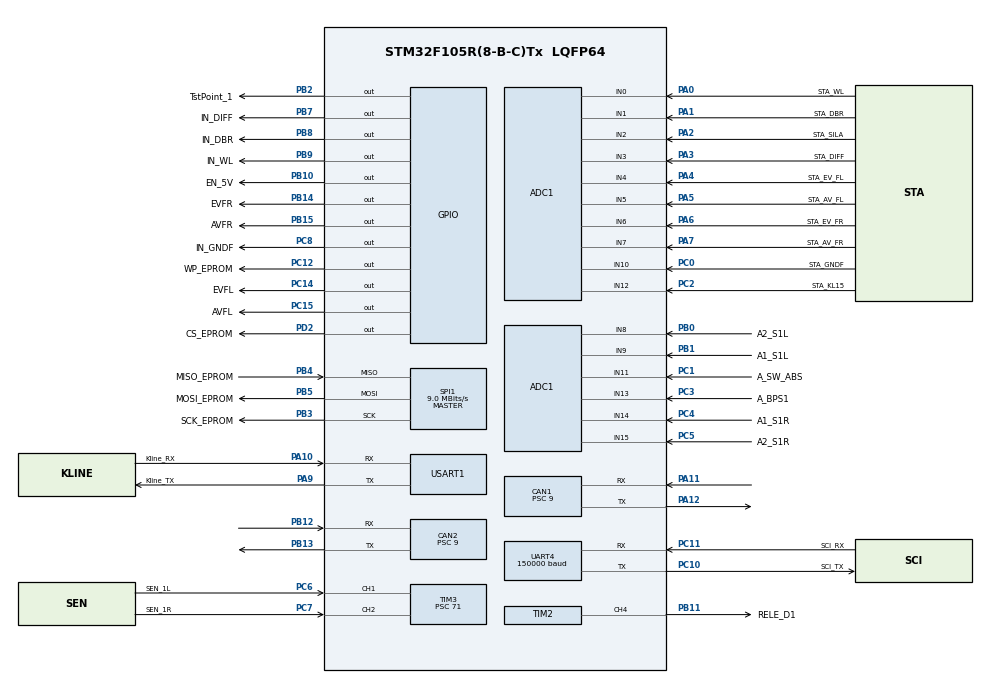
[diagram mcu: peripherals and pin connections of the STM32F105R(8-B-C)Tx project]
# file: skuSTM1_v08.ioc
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ADC1.Channel-0\#ChannelRegularConversion=ADC_CHANNEL_0
ADC1.Channel-1\#ChannelRegularConversion=ADC_CHANNEL_1
ADC1.Channel-10\#ChannelRegularConversion=ADC_CHANNEL_10
ADC1.Channel-11\#ChannelRegularConversion=ADC_CHANNEL_11
ADC1.Channel-12\#ChannelRegularConversion=ADC_CHANNEL_12
ADC1.Channel-13\#ChannelRegularConversion=ADC_CHANNEL_13
ADC1.Channel-14\#ChannelRegularConversion=ADC_CHANNEL_14
ADC1.Channel-15\#ChannelRegularConversion=ADC_CHANNEL_15
ADC1.Channel-2\#ChannelRegularConversion=ADC_CHANNEL_2
ADC1.Channel-3\#ChannelRegularConversion=ADC_CHANNEL_3
ADC1.Channel-4\#ChannelRegularConversion=ADC_CHANNEL_4
ADC1.Channel-5\#ChannelRegularConversion=ADC_CHANNEL_5
ADC1.Channel-6\#ChannelRegularConversion=ADC_CHANNEL_6
ADC1.Channel-7\#ChannelRegularConversion=ADC_CHANNEL_7
ADC1.Channel-8\#ChannelRegularConversion=ADC_CHANNEL_8
ADC1.Channel-9\#ChannelRegularConversion=ADC_CHANNEL_9
ADC1.ContinuousConvMode=DISABLE
ADC1.DataAlign=ADC_DATAALIGN_RIGHT
ADC1.DiscontinuousConvMode=DISABLE
ADC1.EnableAnalogWatchDog=false
ADC1.EnableRegularConversion=ENABLE
ADC1.ExternalTrigConv=ADC_SOFTWARE_START
ADC1.InjNumberOfConversion=0
ADC1.NbrOfConversion=16
ADC1.NbrOfConversionFlag=1
ADC1.Rank-0\#ChannelRegularConversion=1
ADC1.Rank-1\#ChannelRegularConversion=2
ADC1.Rank-10\#ChannelRegularConversion=11
ADC1.Rank-11\#ChannelRegularConversion=12
ADC1.Rank-12\#ChannelRegularConversion=13
ADC1.Rank-13\#ChannelRegularConversion=14
ADC1.Rank-14\#ChannelRegularConversion=15
ADC1.Rank-15\#ChannelRegularConversion=16
ADC1.Rank-2\#ChannelRegularConversion=3
ADC1.Rank-3\#ChannelRegularConversion=4
ADC1.Rank-4\#ChannelRegularConversion=5
ADC1.Rank-5\#ChannelRegularConversion=6
ADC1.Rank-6\#ChannelRegularConversion=7
ADC1.Rank-7\#ChannelRegularConversion=8
ADC1.Rank-8\#ChannelRegularConversion=9
ADC1.Rank-9\#ChannelRegularConversion=10
ADC1.SamplingTime-0\#ChannelRegularConversion=ADC_SAMPLETIME_41CYCLES_5
ADC1.SamplingTime-1\#ChannelRegularConversion=ADC_SAMPLETIME_41CYCLES_5
ADC1.SamplingTime-10\#ChannelRegularConversion=ADC_SAMPLETIME_41CYCLES_5
ADC1.SamplingTime-11\#ChannelRegularConversion=ADC_SAMPLETIME_41CYCLES_5
ADC1.SamplingTime-12\#ChannelRegularConversion=ADC_SAMPLETIME_41CYCLES_5
ADC1.SamplingTime-13\#ChannelRegularConversion=ADC_SAMPLETIME_41CYCLES_5
ADC1.SamplingTime-14\#ChannelRegularConversion=ADC_SAMPLETIME_41CYCLES_5
ADC1.SamplingTime-15\#ChannelRegularConversion=ADC_SAMPLETIME_41CYCLES_5
ADC1.SamplingTime-2\#ChannelRegularConversion=ADC_SAMPLETIME_41CYCLES_5
ADC1.SamplingTime-3\#ChannelRegularConversion=ADC_SAMPLETIME_41CYCLES_5
ADC1.SamplingTime-4\#ChannelRegularConversion=ADC_SAMPLETIME_41CYCLES_5
ADC1.SamplingTime-5\#ChannelRegularConversion=ADC_SAMPLETIME_41CYCLES_5
ADC1.SamplingTime-6\#ChannelRegularConversion=ADC_SAMPLETIME_41CYCLES_5
ADC1.SamplingTime-7\#ChannelRegularConversion=ADC_SAMPLETIME_41CYCLES_5
ADC1.SamplingTime-8\#ChannelRegularConversion=ADC_SAMPLETIME_41CYCLES_5
ADC1.SamplingTime-9\#ChannelRegularConversion=ADC_SAMPLETIME_41CYCLES_5
ADC1.ScanConvMode=ADC_SCAN_ENABLE
ADC1.master=1
CAN1.ABOM=ENABLE
CAN1.BS1=CAN_BS1_8TQ
CAN1.BS2=CAN_BS2_7TQ
CAN1.CalculateTimeBit=4000
CAN1.CalculateTimeQuantum=250.0
CAN1.Prescaler=9
CAN2.ABOM=ENABLE
CAN2.BS1=CAN_BS1_8TQ
CAN2.BS2=CAN_BS2_7TQ
CAN2.CalculateTimeBit=4000
CAN2.CalculateTimeQuantum=250.0
CAN2.Mode=CAN_MODE_NORMAL
CAN2.Prescaler=9
Dma.ADC1.1.Direction=DMA_PERIPH_TO_MEMORY
Dma.ADC1.1.Instance=DMA1_Channel1
Dma.ADC1.1.MemDataAlignment=DMA_MDATAALIGN_HALFWORD
Dma.ADC1.1.MemInc=DMA_MINC_ENABLE
Dma.ADC1.1.Mode=DMA_NORMAL
Dma.ADC1.1.PeriphDataAlignment=DMA_PDATAALIGN_HALFWORD
Dma.ADC1.1.PeriphInc=DMA_PINC_DISABLE
Dma.ADC1.1.Priority=DMA_PRIORITY_LOW
Dma.MEMTOMEM.0.Direction=DMA_MEMORY_TO_MEMORY
Dma.MEMTOMEM.0.Instance=DMA1_Channel6
Dma.MEMTOMEM.0.MemDataAlignment=DMA_MDATAALIGN_WORD
Dma.MEMTOMEM.0.MemInc=DMA_MINC_ENABLE
Dma.MEMTOMEM.0.Mode=DMA_NORMAL
Dma.MEMTOMEM.0.PeriphDataAlignment=DMA_PDATAALIGN_WORD
Dma.MEMTOMEM.0.PeriphInc=DMA_PINC_ENABLE
Dma.MEMTOMEM.0.Priority=DMA_PRIORITY_LOW
Dma.Request0=MEMTOMEM
Dma.Request1=ADC1
Dma.Request2=USART1_RX
Dma.Request3=USART1_TX
Dma.Request4=SPI1_RX
Dma.Request5=SPI1_TX
Dma.Request6=UART4_RX
Dma.Request7=UART4_TX
Dma.SPI1_RX.4.Direction=DMA_PERIPH_TO_MEMORY
Dma.SPI1_RX.4.Instance=DMA1_Channel2
Dma.SPI1_RX.4.MemDataAlignment=DMA_MDATAALIGN_BYTE
Dma.SPI1_RX.4.MemInc=DMA_MINC_ENABLE
Dma.SPI1_RX.4.Mode=DMA_NORMAL
Dma.SPI1_RX.4.PeriphDataAlignment=DMA_PDATAALIGN_BYTE
Dma.SPI1_RX.4.PeriphInc=DMA_PINC_DISABLE
Dma.SPI1_RX.4.Priority=DMA_PRIORITY_LOW
Dma.SPI1_TX.5.Direction=DMA_MEMORY_TO_PERIPH
Dma.SPI1_TX.5.Instance=DMA1_Channel3
Dma.SPI1_TX.5.MemDataAlignment=DMA_MDATAALIGN_BYTE
Dma.SPI1_TX.5.MemInc=DMA_MINC_ENABLE
Dma.SPI1_TX.5.Mode=DMA_NORMAL
Dma.SPI1_TX.5.PeriphDataAlignment=DMA_PDATAALIGN_BYTE
Dma.SPI1_TX.5.PeriphInc=DMA_PINC_DISABLE
Dma.SPI1_TX.5.Priority=DMA_PRIORITY_LOW
Dma.UART4_RX.6.Direction=DMA_PERIPH_TO_MEMORY
Dma.UART4_RX.6.Instance=DMA2_Channel3
Dma.UART4_RX.6.MemDataAlignment=DMA_MDATAALIGN_BYTE
Dma.UART4_RX.6.MemInc=DMA_MINC_ENABLE
Dma.UART4_RX.6.Mode=DMA_NORMAL
Dma.UART4_RX.6.PeriphDataAlignment=DMA_PDATAALIGN_BYTE
Dma.UART4_RX.6.PeriphInc=DMA_PINC_DISABLE
Dma.UART4_RX.6.Priority=DMA_PRIORITY_HIGH
Dma.UART4_TX.7.Direction=DMA_MEMORY_TO_PERIPH
Dma.UART4_TX.7.Instance=DMA2_Channel5
Dma.UART4_TX.7.MemDataAlignment=DMA_MDATAALIGN_BYTE
Dma.UART4_TX.7.MemInc=DMA_MINC_ENABLE
Dma.UART4_TX.7.Mode=DMA_NORMAL
Dma.UART4_TX.7.PeriphDataAlignment=DMA_PDATAALIGN_BYTE
Dma.UART4_TX.7.PeriphInc=DMA_PINC_DISABLE
Dma.UART4_TX.7.Priority=DMA_PRIORITY_MEDIUM
Dma.USART1_RX.2.Direction=DMA_PERIPH_TO_MEMORY
Dma.USART1_RX.2.Instance=DMA1_Channel5
Dma.USART1_RX.2.MemDataAlignment=DMA_MDATAALIGN_BYTE
Dma.USART1_RX.2.MemInc=DMA_MINC_ENABLE
Dma.USART1_RX.2.Mode=DMA_NORMAL
Dma.USART1_RX.2.PeriphDataAlignment=DMA_PDATAALIGN_BYTE
Dma.USART1_RX.2.PeriphInc=DMA_PINC_DISABLE
Dma.USART1_RX.2.Priority=DMA_PRIORITY_HIGH
Dma.USART1_TX.3.Direction=DMA_MEMORY_TO_PERIPH
Dma.USART1_TX.3.Instance=DMA1_Channel4
Dma.USART1_TX.3.MemDataAlignment=DMA_MDATAALIGN_BYTE
Dma.USART1_TX.3.MemInc=DMA_MINC_ENABLE
Dma.USART1_TX.3.Mode=DMA_NORMAL
Dma.USART1_TX.3.PeriphDataAlignment=DMA_PDATAALIGN_BYTE
Dma.USART1_TX.3.PeriphInc=DMA_PINC_DISABLE
Dma.USART1_TX.3.Priority=DMA_PRIORITY_MEDIUM
IWDG.Prescaler=IWDG_PRESCALER_32
Mcu.Family=STM32F1
Mcu.Name=STM32F105R(8-B-C)Tx
Mcu.Package=LQFP64
NVIC.ADC1_2_IRQn=true\:0\:3\:true\:true\:true\:22\:true
NVIC.CAN1_RX0_IRQn=true\:2\:0\:true\:true\:true\:4\:true
NVIC.CAN1_RX1_IRQn=true\:2\:0\:true\:true\:true\:5\:true
NVIC.CAN1_SCE_IRQn=true\:3\:0\:true\:true\:true\:6\:true
NVIC.CAN1_TX_IRQn=true\:3\:0\:true\:true\:true\:3\:true
NVIC.CAN2_RX0_IRQn=true\:2\:0\:true\:true\:true\:13\:true
NVIC.CAN2_RX1_IRQn=true\:2\:0\:true\:true\:true\:15\:true
NVIC.CAN2_SCE_IRQn=true\:3\:0\:true\:true\:true\:14\:true
NVIC.CAN2_TX_IRQn=true\:2\:0\:true\:true\:true\:12\:true
NVIC.DMA1_Channel1_IRQn=true\:0\:3\:true\:true\:true\:2\:false
NVIC.DMA1_Channel2_IRQn=true\:1\:0\:true\:true\:true\:20\:false
NVIC.DMA1_Channel3_IRQn=true\:1\:0\:true\:true\:true\:17\:true
NVIC.DMA1_Channel4_IRQn=true\:2\:2\:true\:true\:true\:21\:true
NVIC.DMA1_Channel5_IRQn=true\:2\:3\:true\:true\:true\:24\:false
NVIC.DMA1_Channel6_IRQn=true\:3\:0\:true\:true\:true\:25\:true
NVIC.DMA2_Channel3_IRQn=true\:0\:1\:false\:true\:true\:9\:false
NVIC.DMA2_Channel5_IRQn=true\:0\:1\:true\:true\:true\:10\:false
NVIC.FLASH_IRQn=true\:1\:0\:true\:true\:true\:1\:true
NVIC.PriorityGroup=NVIC_PRIORITYGROUP_2
NVIC.SPI1_IRQn=true\:1\:0\:true\:true\:true\:19\:true
NVIC.TIM1_CC_IRQn=true\:1\:0\:true\:true\:true\:18\:true
NVIC.TIM3_IRQn=true\:1\:1\:true\:true\:true\:16\:true
NVIC.TIM4_IRQn=true\:1\:2\:true\:true\:true\:23\:true
NVIC.TIM6_IRQn=true\:1\:0\:true\:true\:true\:7\:true
NVIC.TIM7_IRQn=true\:3\:0\:true\:true\:true\:8\:true
NVIC.UART4_IRQn=true\:0\:1\:false\:true\:true\:11\:true
NVIC.USART1_IRQn=true\:2\:0\:true\:false\:true\:true
PA0-WKUP.GPIO_Label=STA_WL
PA0-WKUP.GPIO_Mode=GPIO_MODE_ANALOG
PA0-WKUP.Signal=ADCx_IN0
PA1.GPIO_Label=STA_DBR
PA1.Signal=ADCx_IN1
PA10.GPIO_Label=Kline_RX
PA10.Mode=Asynchronous
PA10.Signal=USART1_RX
PA11.GPIO_Mode=GPIO_MODE_INPUT
PA11.GPIO_PuPd=GPIO_NOPULL
PA11.Mode=Master
PA11.Signal=CAN1_RX
PA12.GPIO_Mode=GPIO_MODE_AF_PP
PA12.GPIO_Speed=GPIO_SPEED_FREQ_HIGH
PA12.Mode=Master
PA12.Signal=CAN1_TX
PA2.GPIO_Label=STA_SILA
PA2.GPIO_Mode=GPIO_MODE_ANALOG
PA2.Signal=ADCx_IN2
PA3.GPIO_Label=STA_DIFF
PA3.Signal=ADCx_IN3
PA4.GPIO_Label=STA_EV_FL
PA4.Signal=ADCx_IN4
PA5.GPIO_Label=STA_AV_FL
PA5.Signal=ADCx_IN5
PA6.GPIO_Label=STA_EV_FR
PA6.Signal=ADCx_IN6
PA7.GPIO_Label=STA_AV_FR
PA7.Signal=ADCx_IN7
PA9.GPIO_Label=Kline_TX
PA9.Mode=Asynchronous
PA9.Signal=USART1_TX
PB0.GPIO_Label=A2_S1L
PB0.Signal=ADCx_IN8
PB1.GPIO_Label=A1_S1L
PB1.Signal=ADCx_IN9
PB10.GPIO_Label=EN_5V
PB10.GPIO_ModeDefaultOutputPP=GPIO_MODE_OUTPUT_PP
PB10.PinState=GPIO_PIN_SET
PB10.Signal=GPIO_Output
PB11.GPIO_Label=RELE_D1
PB11.Signal=S_TIM2_CH4
PB12.GPIO_Mode=GPIO_MODE_INPUT
PB12.Mode=Slave
PB12.Signal=CAN2_RX
PB13.Mode=Slave
PB13.Signal=CAN2_TX
PB14.GPIO_Label=EVFR
PB14.Signal=GPIO_Output
PB15.GPIO_Label=AVFR
PB15.Signal=GPIO_Output
PB2.GPIO_Label=TstPoint_1
PB2.Signal=GPIO_Output
PB3.GPIO_Label=SCK_EPROM
PB3.GPIO_Speed=GPIO_SPEED_FREQ_HIGH
PB3.Mode=Full_Duplex_Master
PB3.Signal=SPI1_SCK
PB4.GPIO_Label=MISO_EPROM
PB4.Mode=Full_Duplex_Master
PB4.Signal=SPI1_MISO
PB5.GPIO_Label=MOSI_EPROM
PB5.Mode=Full_Duplex_Master
PB5.Signal=SPI1_MOSI
PB7.GPIO_Label=IN_DIFF
PB7.Signal=GPIO_Output
PB8.GPIO_Label=IN_DBR
PB8.Signal=GPIO_Output
PB9.GPIO_Label=IN_WL
PB9.PinState=GPIO_PIN_SET
PB9.Signal=GPIO_Output
PC0.GPIO_Label=STA_GNDF
PC0.Signal=ADCx_IN10
PC1.GPIO_Label=A_SW_ABS
PC1.Signal=ADCx_IN11
PC10.GPIO_Label=SCI_TX
PC10.Mode=Asynchronous
PC10.Signal=UART4_TX
PC11.GPIO_Label=SCI_RX
PC11.GPIO_PuPd=GPIO_PULLUP
PC11.Mode=Asynchronous
PC11.Signal=UART4_RX
PC12.GPIO_Label=WP_EPROM
PC12.Signal=GPIO_Output
PC14-OSC32_IN.GPIO_Label=EVFL
PC14-OSC32_IN.Signal=GPIO_Output
PC15-OSC32_OUT.GPIO_Label=AVFL
PC15-OSC32_OUT.Signal=GPIO_Output
PC2.GPIO_Label=STA_KL15
PC2.Signal=ADCx_IN12
PC3.GPIO_Label=A_BPS1
PC3.Signal=ADCx_IN13
PC4.GPIO_Label=A1_S1R
PC4.Signal=ADCx_IN14
PC5.GPIO_Label=A2_S1R
PC5.Signal=ADCx_IN15
PC6.GPIO_Label=SEN_1L
PC6.Signal=S_TIM3_CH1
PC7.GPIO_Label=SEN_1R
PC7.Signal=S_TIM3_CH2
PC8.GPIO_Label=IN_GNDF
PC8.GPIO_Speed=GPIO_SPEED_FREQ_HIGH
PC8.PinState=GPIO_PIN_SET
PC8.Signal=GPIO_Output
PD0-OSC_IN.Mode=HSE-External-Oscillator
PD0-OSC_IN.Signal=RCC_OSC_IN
PD1-OSC_OUT.Mode=HSE-External-Oscillator
PD1-OSC_OUT.Signal=RCC_OSC_OUT
PD2.GPIO_Label=CS_EPROM
PD2.GPIO_ModeDefaultOutputPP=GPIO_MODE_OUTPUT_PP
PD2.PinState=GPIO_PIN_SET
PD2.Signal=GPIO_Output
ProjectManager.HeapSize=0x200
ProjectManager.StackSize=0x400
ProjectManager.TargetToolchain=SW4STM32
RCC.ADCPresc=RCC_ADCPCLK2_DIV4
RCC.AHBFreq_Value=72000000
RCC.APB1CLKDivider=RCC_HCLK_DIV2
RCC.APB1Freq_Value=36000000
RCC.APB1TimFreq_Value=72000000
RCC.APB2CLKDivider=RCC_HCLK_DIV2
RCC.APB2Freq_Value=36000000
RCC.APB2TimFreq_Value=72000000
RCC.DATA_CACHE_ENABLE=1
RCC.HCLKFreq_Value=72000000
RCC.HSEDivPLL=RCC_HSE_PREDIV_DIV5
RCC.HSEUsed=1
RCC.HSE_Timout=10
RCC.INSTRUCTION_CACHE_ENABLE=1
RCC.LSE_Timout=10
RCC.PLL2Mul=RCC_PLL2_MUL10
RCC.PLLMUL=RCC_PLL_MUL9
RCC.PLLSourceVirtual=RCC_PLLSOURCE_HSE
RCC.PREFETCH_ENABLE=1
RCC.Prediv1Source=RCC_PREDIV1_SOURCE_PLL2
RCC.Prediv2=RCC_HSE_PREDIV2_DIV2
RCC.SYSCLKFreq_VALUE=72000000
RCC.SYSCLKSource=RCC_SYSCLKSOURCE_PLLCLK
RCC.USBFreq_Value=48000000
SH.ADCx_IN0.0=ADC1_IN0,IN0
SH.ADCx_IN1.0=ADC1_IN1,IN1
SH.ADCx_IN10.0=ADC1_IN10,IN10
SH.ADCx_IN11.0=ADC1_IN11,IN11
SH.ADCx_IN12.0=ADC1_IN12,IN12
SH.ADCx_IN13.0=ADC1_IN13,IN13
SH.ADCx_IN14.0=ADC1_IN14,IN14
SH.ADCx_IN15.0=ADC1_IN15,IN15
SH.ADCx_IN2.0=ADC1_IN2,IN2
SH.ADCx_IN3.0=ADC1_IN3,IN3
SH.ADCx_IN4.0=ADC1_IN4,IN4
SH.ADCx_IN5.0=ADC1_IN5,IN5
SH.ADCx_IN6.0=ADC1_IN6,IN6
SH.ADCx_IN7.0=ADC1_IN7,IN7
SH.ADCx_IN8.0=ADC1_IN8,IN8
SH.ADCx_IN9.0=ADC1_IN9,IN9
SH.S_TIM2_CH4.0=TIM2_CH4,PWM Generation4 CH4
SH.S_TIM3_CH1.0=TIM3_CH1,Input_Capture1_from_TI1
SH.S_TIM3_CH2.0=TIM3_CH2,Input_Capture2_from_TI2
SPI1.BaudRatePrescaler=SPI_BAUDRATEPRESCALER_4
SPI1.CLKPhase=SPI_PHASE_1EDGE
SPI1.CLKPolarity=SPI_POLARITY_LOW
SPI1.CalculateBaudRate=9.0 MBits/s
SPI1.Direction=SPI_DIRECTION_2LINES
SPI1.Mode=SPI_MODE_MASTER
SPI1.VirtualType=VM_MASTER
TIM1.Channel-Output\ Compare1\ No\ Output=TIM_CHANNEL_1
TIM1.Channel-Output\ Compare2\ No\ Output=TIM_CHANNEL_2
TIM1.Channel-Output\ Compare3\ No\ Output=TIM_CHANNEL_3
TIM1.Channel-Output\ Compare4\ No\ Output=TIM_CHANNEL_4
TIM1.Period=0xFFFF
TIM1.Prescaler=71
TIM2.Channel-PWM\ Generation4\ CH4=TIM_CHANNEL_4
TIM2.OCPolarity_4=TIM_OCPOLARITY_LOW
TIM2.Period=3600
TIM2.Prescaler=0
TIM3.AutoReloadPreload=TIM_AUTORELOAD_PRELOAD_DISABLE
TIM3.Channel-Input_Capture1_from_TI1=TIM_CHANNEL_1
TIM3.Channel-Input_Capture2_from_TI2=TIM_CHANNEL_2
TIM3.ICFilter_CH1=15
TIM3.ICFilter_CH2=15
TIM3.ICPolarity_CH1=TIM_INPUTCHANNELPOLARITY_FALLING
TIM3.ICPolarity_CH2=TIM_INPUTCHANNELPOLARITY_FALLING
TIM3.Period=0xFFFF
TIM3.Prescaler=71
TIM3.TIM_MasterSlaveMode=TIM_MASTERSLAVEMODE_DISABLE
TIM4.AutoReloadPreload=TIM_AUTORELOAD_PRELOAD_ENABLE
TIM4.Channel-Output\ Compare3\ No\ Output=TIM_CHANNEL_3
TIM4.Period=0xFFFF
TIM4.Prescaler=71
TIM4.Pulse-Output\ Compare3\ No\ Output=300
TIM6.AutoReloadPreload=TIM_AUTORELOAD_PRELOAD_DISABLE
TIM6.Period=5000
TIM6.Prescaler=71
TIM6.TIM_MasterOutputTrigger=TIM_TRGO_RESET
TIM7.Period=100
TIM7.Prescaler=71
UART4.BaudRate=150000
UART4.VirtualMode=Asynchronous
USART1.VirtualMode=VM_ASYNC
VP_ADC1_TempSens_Input.Mode=IN-TempSens
VP_CRC_VS_CRC.Mode=CRC_Activate
VP_IWDG_VS_IWDG.Mode=IWDG_Activate
VP_SYS_VS_ND.Mode=No_Debug
VP_TIM1_VS_ClockSourceINT.Mode=Internal
VP_TIM1_VS_no_output1.Mode=Output Compare1 No Output
VP_TIM1_VS_no_output2.Mode=Output Compare2 No Output
VP_TIM1_VS_no_output3.Mode=Output Compare3 No Output
VP_TIM1_VS_no_output4.Mode=Output Compare4 No Output
VP_TIM2_VS_ClockSourceINT.Mode=Internal
VP_TIM3_VS_ClockSourceINT.Mode=Internal
VP_TIM4_VS_ClockSourceINT.Mode=Internal
VP_TIM4_VS_no_output3.Mode=Output Compare3 No Output
VP_TIM6_VS_ClockSourceINT.Mode=Enable_Timer
VP_TIM7_VS_ClockSourceINT.Mode=Enable_Timer
board=skuSTM1_v08

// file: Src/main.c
/**
  ******************************************************************************
  * @file           : main.c
  * @brief          : Main program body
  ******************************************************************************
  ** This notice applies to any and all portions of this file
  * that are not between comment pairs USER CODE BEGIN and
  * USER CODE END. Other portions of this file, whether
  * inserted by the user or by software development tools
  * are owned by their respective copyright owners.
  *
  * COPYRIGHT(c) 2025 STMicroelectronics
  *
  * Redistribution and use in source and binary forms, with or without modification,
  * are permitted provided that the following conditions are met:
  *   1. Redistributions of source code must retain the above copyright notice,
  *      this list of conditions and the following disclaimer.
  *   2. Redistributions in binary form must reproduce the above copyright notice,
  *      this list of conditions and the following disclaimer in the documentation
  *      and/or other materials provided with the distribution.
  *   3. Neither the name of STMicroelectronics nor the names of its contributors
  *      may be used to endorse or promote products derived from this software
  *      without specific prior written permission.
  *
  * THIS SOFTWARE IS PROVIDED BY THE COPYRIGHT HOLDERS AND CONTRIBUTORS "AS IS"
  * AND ANY EXPRESS OR IMPLIED WARRANTIES, INCLUDING, BUT NOT LIMITED TO, THE
  * IMPLIED WARRANTIES OF MERCHANTABILITY AND FITNESS FOR A PARTICULAR PURPOSE ARE
  * DISCLAIMED. IN NO EVENT SHALL THE COPYRIGHT HOLDER OR CONTRIBUTORS BE LIABLE
  * FOR ANY DIRECT, INDIRECT, INCIDENTAL, SPECIAL, EXEMPLARY, OR CONSEQUENTIAL
  * DAMAGES (INCLUDING, BUT NOT LIMITED TO, PROCUREMENT OF SUBSTITUTE GOODS OR
  * SERVICES; LOSS OF USE, DATA, OR PROFITS; OR BUSINESS INTERRUPTION) HOWEVER
  * CAUSED AND ON ANY THEORY OF LIABILITY, WHETHER IN CONTRACT, STRICT LIABILITY,
  * OR TORT (INCLUDING NEGLIGENCE OR OTHERWISE) ARISING IN ANY WAY OUT OF THE USE
  * OF THIS SOFTWARE, EVEN IF ADVISED OF THE POSSIBILITY OF SUCH DAMAGE.
  *
  ******************************************************************************
  */
#include "main.h"
#include "stm32f1xx_hal.h"

/* USER CODE BEGIN Includes */
#include "MyTypeDef.h"
#include "MyPGM.h"
#include "MySystem.h"
#include "MyFunc.h"
#include "MyVAR.h"

/* USER CODE END Includes */

ADC_HandleTypeDef hadc1;
DMA_HandleTypeDef hdma_adc1;

CAN_HandleTypeDef hcan1;
CAN_HandleTypeDef hcan2;

CRC_HandleTypeDef hcrc;

IWDG_HandleTypeDef hiwdg;

SPI_HandleTypeDef hspi1;
DMA_HandleTypeDef hdma_spi1_rx;
DMA_HandleTypeDef hdma_spi1_tx;

TIM_HandleTypeDef htim1;
TIM_HandleTypeDef htim2;
TIM_HandleTypeDef htim3;
TIM_HandleTypeDef htim4;
TIM_HandleTypeDef htim6;
TIM_HandleTypeDef htim7;

UART_HandleTypeDef huart4;
UART_HandleTypeDef huart1;
DMA_HandleTypeDef hdma_uart4_rx;
DMA_HandleTypeDef hdma_uart4_tx;
DMA_HandleTypeDef hdma_usart1_rx;
DMA_HandleTypeDef hdma_usart1_tx;

DMA_HandleTypeDef hdma_memtomem_dma1_channel6;

/* USER CODE BEGIN PV */
/* Private variables ---------------------------------------------------------*/

/* USER CODE END PV */

void SystemClock_Config(void);
static void MX_GPIO_Init(void);
static void MX_DMA_Init(void);
static void MX_CRC_Init(void);
static void MX_ADC1_Init(void);
static void MX_TIM6_Init(void);
static void MX_UART4_Init(void);
static void MX_TIM7_Init(void);
static void MX_TIM1_Init(void);
static void MX_CAN1_Init(void);
static void MX_IWDG_Init(void);
static void MX_CAN2_Init(void);
static void MX_TIM3_Init(void);
static void MX_TIM4_Init(void);
static void MX_SPI1_Init(void);
static void MX_USART1_UART_Init(void);
static void MX_TIM2_Init(void);
static void MX_NVIC_Init(void);

void HAL_TIM_MspPostInit(TIM_HandleTypeDef *htim);

/* USER CODE BEGIN PFP */
/* Private function prototypes -----------------------------------------------*/

/* USER CODE END PFP */

/* USER CODE BEGIN 0 */
extern uint8_t  PGM_Active;
extern uint8_t  CANS_InitState;
/* USER CODE END 0 */

int main(void)
{

  /* MCU Configuration----------------------------------------------------------*/

  /* Reset of all peripherals, Initializes the Flash interface and the Systick. */
  HAL_Init();

  /* USER CODE BEGIN Init */
#ifdef __MC_GD
uint32_t *FMC_WSEN;
      FMC_WSEN = (uint32_t*)0x400220FC;
      FLASH->KEYR = FLASH_KEY1;
      FLASH->KEYR = FLASH_KEY2;
      *FMC_WSEN = (uint32_t)1U;
#endif
  /* USER CODE END Init */

  /* Configure the system clock */
  SystemClock_Config();

  /* USER CODE BEGIN SysInit */
  // устанавливаем STA_CANTL_Pin для установки компаратора в 1
  // если резистор R152 0 (27Om)
/*GPIO_InitTypeDef GPIO_InitStruct;
      __HAL_RCC_GPIOB_CLK_ENABLE();
	  GPIO_InitStruct.Pin = CANTL_EN_Pin|STA_CANTL_Pin|TstPoint_2_Pin;
	  GPIO_InitStruct.Mode = GPIO_MODE_OUTPUT_PP;
	  GPIO_InitStruct.Speed = GPIO_SPEED_FREQ_LOW;
	  HAL_GPIO_Init(GPIOB, &GPIO_InitStruct);

      HAL_GPIO_WritePin(GPIOB, STA_CANTL_Pin, GPIO_PIN_SET);
      HAL_GPIO_WritePin(GPIOB, CANTL_EN_Pin, GPIO_PIN_SET);
	  while(!HAL_GPIO_ReadPin(GPIOB, CANT_RX_Pin));
*/
  /* USER CODE END SysInit */

  /* Initialize all configured peripherals */
  MX_GPIO_Init();
  MX_DMA_Init();
  MX_CRC_Init();
  MX_ADC1_Init();
  MX_TIM6_Init();
  MX_UART4_Init();
  MX_TIM7_Init();
  MX_TIM1_Init();
  MX_CAN1_Init();
  MX_IWDG_Init();
  MX_CAN2_Init();
  MX_TIM3_Init();
  MX_TIM4_Init();
  MX_SPI1_Init();
  MX_USART1_UART_Init();
  MX_TIM2_Init();

  /* Initialize interrupts */
  MX_NVIC_Init();
  /* USER CODE BEGIN 2 */
  CANS_InitState = HAL_CAN_GetState(&hcan1);

  if(!PGM_Active)  MyHallTab[14](); // My_Init();

  /* USER CODE END 2 */

  /* Infinite loop */
  while (1)
  {

  /* USER CODE BEGIN 3 */
	if(PGM_Active)
	{ // активен программатор
		 MyHallTab[19](); //My_UpGrade_STM();
	  // выход отсюда в программаторах Jump_To_App()
	}
	else MyHallTab[15](); //   My_Main();
  }
  /* USER CODE END 3 */

}

void SystemClock_Config(void)
{

  RCC_OscInitTypeDef RCC_OscInitStruct;
  RCC_ClkInitTypeDef RCC_ClkInitStruct;
  RCC_PeriphCLKInitTypeDef PeriphClkInit;

    /**Initializes the CPU, AHB and APB busses clocks
    */
  RCC_OscInitStruct.OscillatorType = RCC_OSCILLATORTYPE_LSI|RCC_OSCILLATORTYPE_HSE;
  RCC_OscInitStruct.HSEState = RCC_HSE_ON;
  RCC_OscInitStruct.HSEPredivValue = RCC_HSE_PREDIV_DIV4;
  RCC_OscInitStruct.HSIState = RCC_HSI_ON;
  RCC_OscInitStruct.LSIState = RCC_LSI_ON;
  RCC_OscInitStruct.Prediv1Source = RCC_PREDIV1_SOURCE_PLL2;
  RCC_OscInitStruct.PLL.PLLState = RCC_PLL_ON;
  RCC_OscInitStruct.PLL.PLLSource = RCC_PLLSOURCE_HSE;
  RCC_OscInitStruct.PLL.PLLMUL = RCC_PLL_MUL9;
  RCC_OscInitStruct.PLL2.PLL2State = RCC_PLL2_ON;
  RCC_OscInitStruct.PLL2.PLL2MUL = RCC_PLL2_MUL12;
  RCC_OscInitStruct.PLL2.HSEPrediv2Value = RCC_HSE_PREDIV2_DIV2;
  if (HAL_RCC_OscConfig(&RCC_OscInitStruct) != HAL_OK)
  {
    _Error_Handler(__FILE__, __LINE__);
  }

    /**Initializes the CPU, AHB and APB busses clocks
    */
  RCC_ClkInitStruct.ClockType = RCC_CLOCKTYPE_HCLK|RCC_CLOCKTYPE_SYSCLK
                              |RCC_CLOCKTYPE_PCLK1|RCC_CLOCKTYPE_PCLK2;
  RCC_ClkInitStruct.SYSCLKSource = RCC_SYSCLKSOURCE_PLLCLK;
  RCC_ClkInitStruct.AHBCLKDivider = RCC_SYSCLK_DIV1;
  RCC_ClkInitStruct.APB1CLKDivider = RCC_HCLK_DIV2;
  RCC_ClkInitStruct.APB2CLKDivider = RCC_HCLK_DIV2;

  if (HAL_RCC_ClockConfig(&RCC_ClkInitStruct, FLASH_LATENCY_2) != HAL_OK)
  {
    _Error_Handler(__FILE__, __LINE__);
  }

  PeriphClkInit.PeriphClockSelection = RCC_PERIPHCLK_ADC;
  PeriphClkInit.AdcClockSelection = RCC_ADCPCLK2_DIV6;
  if (HAL_RCCEx_PeriphCLKConfig(&PeriphClkInit) != HAL_OK)
  {
    _Error_Handler(__FILE__, __LINE__);
  }

    /**Configure the Systick interrupt time
    */
  HAL_SYSTICK_Config(HAL_RCC_GetHCLKFreq()/1000);

    /**Configure the Systick
    */
  HAL_SYSTICK_CLKSourceConfig(SYSTICK_CLKSOURCE_HCLK);

    /**Configure the Systick interrupt time
    */
  __HAL_RCC_PLLI2S_ENABLE();

  /* SysTick_IRQn interrupt configuration */
//  HAL_NVIC_SetPriority(SysTick_IRQn, 3, 0);
}

/**
  * @brief NVIC Configuration.
  * @retval None
  */
static void MX_NVIC_Init(void)
{
  /* FLASH_IRQn interrupt configuration */
  HAL_NVIC_SetPriority(FLASH_IRQn, 1, 0);
  HAL_NVIC_EnableIRQ(FLASH_IRQn);

  /* ADC1_2_IRQn interrupt configuration */
  HAL_NVIC_SetPriority(ADC1_2_IRQn, 0, 3);
  HAL_NVIC_EnableIRQ(ADC1_2_IRQn);
  /* DMA1_Channel1_IRQn interrupt configuration */
  HAL_NVIC_SetPriority(DMA1_Channel1_IRQn, 0, 3);
  HAL_NVIC_EnableIRQ(DMA1_Channel1_IRQn);

  /* CAN1_TX_IRQn interrupt configuration */
  HAL_NVIC_SetPriority(CAN1_TX_IRQn, 3, 0);
  HAL_NVIC_EnableIRQ(CAN1_TX_IRQn);
  /* CAN1_RX0_IRQn interrupt configuration */
  HAL_NVIC_SetPriority(CAN1_RX0_IRQn, 2, 0);
  HAL_NVIC_EnableIRQ(CAN1_RX0_IRQn);
  /* CAN1_RX1_IRQn interrupt configuration */
  HAL_NVIC_SetPriority(CAN1_RX1_IRQn, 2, 0);
  HAL_NVIC_EnableIRQ(CAN1_RX1_IRQn);
  /* CAN1_SCE_IRQn interrupt configuration */
  HAL_NVIC_SetPriority(CAN1_SCE_IRQn, 3, 0);
  HAL_NVIC_EnableIRQ(CAN1_SCE_IRQn);

  /* TIM6_IRQn interrupt configuration */
  HAL_NVIC_SetPriority(TIM6_IRQn, 1, 0);
  HAL_NVIC_EnableIRQ(TIM6_IRQn);
  /* TIM7_IRQn interrupt configuration */
  HAL_NVIC_SetPriority(TIM7_IRQn, 3, 0);
  HAL_NVIC_EnableIRQ(TIM7_IRQn);

  /* CAN2_TX_IRQn interrupt configuration */
  HAL_NVIC_SetPriority(CAN2_TX_IRQn, 2, 0);
  HAL_NVIC_EnableIRQ(CAN2_TX_IRQn);
  /* CAN2_RX0_IRQn interrupt configuration */
  HAL_NVIC_SetPriority(CAN2_RX0_IRQn, 2, 0);
  HAL_NVIC_EnableIRQ(CAN2_RX0_IRQn);
  /* CAN2_SCE_IRQn interrupt configuration */
  HAL_NVIC_SetPriority(CAN2_SCE_IRQn, 3, 0);
  HAL_NVIC_EnableIRQ(CAN2_SCE_IRQn);
  /* CAN2_RX1_IRQn interrupt configuration */
  HAL_NVIC_SetPriority(CAN2_RX1_IRQn, 2, 0);
  HAL_NVIC_EnableIRQ(CAN2_RX1_IRQn);

  /* TIM3_IRQn interrupt configuration */
  HAL_NVIC_SetPriority(TIM3_IRQn, 1, 1);
  HAL_NVIC_EnableIRQ(TIM3_IRQn);
  /* TIM1_CC_IRQn interrupt configuration */
  HAL_NVIC_SetPriority(TIM1_CC_IRQn, 1, 0);
  HAL_NVIC_EnableIRQ(TIM1_CC_IRQn);

  /* SPI1_IRQn interrupt configuration */
  HAL_NVIC_SetPriority(SPI1_IRQn, 1, 0);
  HAL_NVIC_EnableIRQ(SPI1_IRQn);
  /* DMA1_Channel2_IRQn interrupt configuration */
  HAL_NVIC_SetPriority(DMA1_Channel2_IRQn, 1, 0);
  HAL_NVIC_EnableIRQ(DMA1_Channel2_IRQn);
  /* DMA1_Channel3_IRQn interrupt configuration */
  HAL_NVIC_SetPriority(DMA1_Channel3_IRQn, 1, 0);
  HAL_NVIC_EnableIRQ(DMA1_Channel3_IRQn);

  /* TIM4_IRQn interrupt configuration */
  HAL_NVIC_SetPriority(TIM4_IRQn, 2, 2);
  HAL_NVIC_EnableIRQ(TIM4_IRQn);
  /* DMA1_Channel6_IRQn interrupt configuration */
  HAL_NVIC_SetPriority(DMA1_Channel6_IRQn, 3, 3);
  HAL_NVIC_EnableIRQ(DMA1_Channel6_IRQn);
  /* EXTI9_5_IRQn interrupt configuration */
  HAL_NVIC_SetPriority(EXTI9_5_IRQn, 0, 2);
  HAL_NVIC_EnableIRQ(EXTI9_5_IRQn);
}

/* ADC1 init function */
static void MX_ADC1_Init(void)
{

  ADC_ChannelConfTypeDef sConfig;

    /**Common config
    */
  hadc1.Instance = ADC1;
  hadc1.Init.ScanConvMode = ADC_SCAN_ENABLE;
  hadc1.Init.ContinuousConvMode = DISABLE;
  hadc1.Init.DiscontinuousConvMode = DISABLE;
  hadc1.Init.ExternalTrigConv = ADC_SOFTWARE_START;
  hadc1.Init.DataAlign = ADC_DATAALIGN_RIGHT;
  hadc1.Init.NbrOfConversion = 16;
  if (HAL_ADC_Init(&hadc1) != HAL_OK)
  {
    _Error_Handler(__FILE__, __LINE__);
  }

    /**Configure Regular Channel
    */
  sConfig.Channel = ADC_CHANNEL_0;
  sConfig.Rank = ADC_REGULAR_RANK_1;
  sConfig.SamplingTime = ADC_SAMPLETIME_41CYCLES_5;
  if (HAL_ADC_ConfigChannel(&hadc1, &sConfig) != HAL_OK)
  {
    _Error_Handler(__FILE__, __LINE__);
  }

    /**Configure Regular Channel
    */
  sConfig.Channel = ADC_CHANNEL_1;
  sConfig.Rank = ADC_REGULAR_RANK_2;
  if (HAL_ADC_ConfigChannel(&hadc1, &sConfig) != HAL_OK)
  {
    _Error_Handler(__FILE__, __LINE__);
  }

    /**Configure Regular Channel
    */
  sConfig.Channel = ADC_CHANNEL_2;
  sConfig.Rank = ADC_REGULAR_RANK_3;
  if (HAL_ADC_ConfigChannel(&hadc1, &sConfig) != HAL_OK)
  {
    _Error_Handler(__FILE__, __LINE__);
  }

    /**Configure Regular Channel
    */
  sConfig.Channel = ADC_CHANNEL_3;
  sConfig.Rank = ADC_REGULAR_RANK_4;
  if (HAL_ADC_ConfigChannel(&hadc1, &sConfig) != HAL_OK)
  {
    _Error_Handler(__FILE__, __LINE__);
  }

    /**Configure Regular Channel
    */
  sConfig.Channel = ADC_CHANNEL_4;
  sConfig.Rank = ADC_REGULAR_RANK_5;
  if (HAL_ADC_ConfigChannel(&hadc1, &sConfig) != HAL_OK)
  {
    _Error_Handler(__FILE__, __LINE__);
  }

    /**Configure Regular Channel
    */
  sConfig.Channel = ADC_CHANNEL_5;
  sConfig.Rank = ADC_REGULAR_RANK_6;
  if (HAL_ADC_ConfigChannel(&hadc1, &sConfig) != HAL_OK)
  {
    _Error_Handler(__FILE__, __LINE__);
  }

    /**Configure Regular Channel
    */
  sConfig.Channel = ADC_CHANNEL_6;
  sConfig.Rank = ADC_REGULAR_RANK_7;
  if (HAL_ADC_ConfigChannel(&hadc1, &sConfig) != HAL_OK)
  {
    _Error_Handler(__FILE__, __LINE__);
  }

    /**Configure Regular Channel
    */
  sConfig.Channel = ADC_CHANNEL_7;
  sConfig.Rank = ADC_REGULAR_RANK_8;
  if (HAL_ADC_ConfigChannel(&hadc1, &sConfig) != HAL_OK)
  {
    _Error_Handler(__FILE__, __LINE__);
  }

    /**Configure Regular Channel
    */
  sConfig.Channel = ADC_CHANNEL_8;
  sConfig.Rank = ADC_REGULAR_RANK_9;
  if (HAL_ADC_ConfigChannel(&hadc1, &sConfig) != HAL_OK)
  {
    _Error_Handler(__FILE__, __LINE__);
  }

    /**Configure Regular Channel
    */
  sConfig.Channel = ADC_CHANNEL_9;
  sConfig.Rank = ADC_REGULAR_RANK_10;
  if (HAL_ADC_ConfigChannel(&hadc1, &sConfig) != HAL_OK)
  {
    _Error_Handler(__FILE__, __LINE__);
  }

    /**Configure Regular Channel
    */
  sConfig.Channel = ADC_CHANNEL_10;
  sConfig.Rank = ADC_REGULAR_RANK_11;
  if (HAL_ADC_ConfigChannel(&hadc1, &sConfig) != HAL_OK)
  {
    _Error_Handler(__FILE__, __LINE__);
  }

    /**Configure Regular Channel
    */
  sConfig.Channel = ADC_CHANNEL_11;
  sConfig.Rank = ADC_REGULAR_RANK_12;
  if (HAL_ADC_ConfigChannel(&hadc1, &sConfig) != HAL_OK)
  {
    _Error_Handler(__FILE__, __LINE__);
  }

    /**Configure Regular Channel
    */
  sConfig.Channel = ADC_CHANNEL_12;
  sConfig.Rank = ADC_REGULAR_RANK_13;
  if (HAL_ADC_ConfigChannel(&hadc1, &sConfig) != HAL_OK)
  {
    _Error_Handler(__FILE__, __LINE__);
  }

    /**Configure Regular Channel
    */
  sConfig.Channel = ADC_CHANNEL_13;
  sConfig.Rank = ADC_REGULAR_RANK_14;
  if (HAL_ADC_ConfigChannel(&hadc1, &sConfig) != HAL_OK)
  {
    _Error_Handler(__FILE__, __LINE__);
  }

    /**Configure Regular Channel
    */
  sConfig.Channel = ADC_CHANNEL_14;
  sConfig.Rank = ADC_REGULAR_RANK_15;
  if (HAL_ADC_ConfigChannel(&hadc1, &sConfig) != HAL_OK)
  {
    _Error_Handler(__FILE__, __LINE__);
  }

    /**Configure Regular Channel
    */
  sConfig.Channel = ADC_CHANNEL_15;
  sConfig.Rank = ADC_REGULAR_RANK_16;
  if (HAL_ADC_ConfigChannel(&hadc1, &sConfig) != HAL_OK)
  {
    _Error_Handler(__FILE__, __LINE__);
  }

}

/* CAN1 init function */
static void MX_CAN1_Init(void)
{

  hcan1.Instance = CAN1;
  hcan1.Init.Prescaler = 12;
  hcan1.Init.Mode = CAN_MODE_NORMAL;
  hcan1.Init.SJW = CAN_SJW_1TQ;
  hcan1.Init.BS1 = CAN_BS1_9TQ;
  hcan1.Init.BS2 = CAN_BS2_8TQ;
  hcan1.Init.TTCM = DISABLE;
  hcan1.Init.ABOM = ENABLE;
  hcan1.Init.AWUM = DISABLE;
  hcan1.Init.NART = DISABLE;
  hcan1.Init.RFLM = DISABLE;
  hcan1.Init.TXFP = DISABLE;
  if (HAL_CAN_Init(&hcan1) != HAL_OK)
  {
    _Error_Handler(__FILE__, __LINE__);
  }

}

/* CAN2 init function */
static void MX_CAN2_Init(void)
{

  hcan2.Instance = CAN2;
  hcan2.Init.Prescaler = 12;
  hcan2.Init.Mode = CAN_MODE_NORMAL;
  hcan2.Init.SJW = CAN_SJW_1TQ;
  hcan2.Init.BS1 = CAN_BS1_9TQ;
  hcan2.Init.BS2 = CAN_BS2_8TQ;
  hcan2.Init.TTCM = DISABLE;
  hcan2.Init.ABOM = ENABLE;
  hcan2.Init.AWUM = DISABLE;
  hcan2.Init.NART = DISABLE;
  hcan2.Init.RFLM = DISABLE;
  hcan2.Init.TXFP = DISABLE;
  if (HAL_CAN_Init(&hcan2) != HAL_OK)
  {
    _Error_Handler(__FILE__, __LINE__);
  }

}

/* CRC init function */
static void MX_CRC_Init(void)
{

  hcrc.Instance = CRC;
  if (HAL_CRC_Init(&hcrc) != HAL_OK)
  {
    _Error_Handler(__FILE__, __LINE__);
  }

}

/* IWDG init function */
static void MX_IWDG_Init(void)
{

  hiwdg.Instance = IWDG;
  hiwdg.Init.Prescaler = IWDG_PRESCALER_32;
  hiwdg.Init.Reload = 4095;
  if (HAL_IWDG_Init(&hiwdg) != HAL_OK)
  {
    _Error_Handler(__FILE__, __LINE__);
  }

}

/* SPI1 init function */
static void MX_SPI1_Init(void)
{

  /* SPI1 parameter configuration*/
  hspi1.Instance = SPI1;
  hspi1.Init.Mode = SPI_MODE_MASTER;
  hspi1.Init.Direction = SPI_DIRECTION_2LINES;
  hspi1.Init.DataSize = SPI_DATASIZE_8BIT;
  hspi1.Init.CLKPolarity = SPI_POLARITY_LOW;
  hspi1.Init.CLKPhase = SPI_PHASE_1EDGE;
  hspi1.Init.NSS = SPI_NSS_SOFT;
  hspi1.Init.BaudRatePrescaler = SPI_BAUDRATEPRESCALER_4;
  hspi1.Init.FirstBit = SPI_FIRSTBIT_MSB;
  hspi1.Init.TIMode = SPI_TIMODE_DISABLE;
  hspi1.Init.CRCCalculation = SPI_CRCCALCULATION_DISABLE;
  hspi1.Init.CRCPolynomial = 10;
  if (HAL_SPI_Init(&hspi1) != HAL_OK)
  {
    _Error_Handler(__FILE__, __LINE__);
  }

}

/* TIM1 init function */
static void MX_TIM1_Init(void)
{

  TIM_ClockConfigTypeDef sClockSourceConfig;
  TIM_MasterConfigTypeDef sMasterConfig;
  TIM_OC_InitTypeDef sConfigOC;
  TIM_BreakDeadTimeConfigTypeDef sBreakDeadTimeConfig;

  htim1.Instance = TIM1;
  htim1.Init.Prescaler = 107;//71;
  htim1.Init.CounterMode = TIM_COUNTERMODE_UP;
  htim1.Init.Period = 0xFFFF;
  htim1.Init.ClockDivision = TIM_CLOCKDIVISION_DIV1;
  htim1.Init.RepetitionCounter = 0;
  htim1.Init.AutoReloadPreload = TIM_AUTORELOAD_PRELOAD_DISABLE;
  if (HAL_TIM_Base_Init(&htim1) != HAL_OK)
  {
    _Error_Handler(__FILE__, __LINE__);
  }

  sClockSourceConfig.ClockSource = TIM_CLOCKSOURCE_INTERNAL;
  if (HAL_TIM_ConfigClockSource(&htim1, &sClockSourceConfig) != HAL_OK)
  {
    _Error_Handler(__FILE__, __LINE__);
  }

  if (HAL_TIM_OC_Init(&htim1) != HAL_OK)
  {
    _Error_Handler(__FILE__, __LINE__);
  }

  sMasterConfig.MasterOutputTrigger = TIM_TRGO_RESET;
  sMasterConfig.MasterSlaveMode = TIM_MASTERSLAVEMODE_DISABLE;
  if (HAL_TIMEx_MasterConfigSynchronization(&htim1, &sMasterConfig) != HAL_OK)
  {
    _Error_Handler(__FILE__, __LINE__);
  }

  sConfigOC.OCMode = TIM_OCMODE_TIMING;
  sConfigOC.Pulse = 0;
  sConfigOC.OCPolarity = TIM_OCPOLARITY_HIGH;
  sConfigOC.OCNPolarity = TIM_OCNPOLARITY_HIGH;
  sConfigOC.OCFastMode = TIM_OCFAST_DISABLE;
  sConfigOC.OCIdleState = TIM_OCIDLESTATE_RESET;
  sConfigOC.OCNIdleState = TIM_OCNIDLESTATE_RESET;
  if (HAL_TIM_OC_ConfigChannel(&htim1, &sConfigOC, TIM_CHANNEL_1) != HAL_OK)
  {
    _Error_Handler(__FILE__, __LINE__);
  }

  if (HAL_TIM_OC_ConfigChannel(&htim1, &sConfigOC, TIM_CHANNEL_2) != HAL_OK)
  {
    _Error_Handler(__FILE__, __LINE__);
  }

  if (HAL_TIM_OC_ConfigChannel(&htim1, &sConfigOC, TIM_CHANNEL_3) != HAL_OK)
  {
    _Error_Handler(__FILE__, __LINE__);
  }

  if (HAL_TIM_OC_ConfigChannel(&htim1, &sConfigOC, TIM_CHANNEL_4) != HAL_OK)
  {
    _Error_Handler(__FILE__, __LINE__);
  }

  sBreakDeadTimeConfig.OffStateRunMode = TIM_OSSR_DISABLE;
  sBreakDeadTimeConfig.OffStateIDLEMode = TIM_OSSI_DISABLE;
  sBreakDeadTimeConfig.LockLevel = TIM_LOCKLEVEL_OFF;
  sBreakDeadTimeConfig.DeadTime = 0;
  sBreakDeadTimeConfig.BreakState = TIM_BREAK_DISABLE;
  sBreakDeadTimeConfig.BreakPolarity = TIM_BREAKPOLARITY_HIGH;
  sBreakDeadTimeConfig.AutomaticOutput = TIM_AUTOMATICOUTPUT_DISABLE;
  if (HAL_TIMEx_ConfigBreakDeadTime(&htim1, &sBreakDeadTimeConfig) != HAL_OK)
  {
    _Error_Handler(__FILE__, __LINE__);
  }

}

/* TIM2 init function */
static void MX_TIM2_Init(void)
{

  TIM_ClockConfigTypeDef sClockSourceConfig;
  TIM_MasterConfigTypeDef sMasterConfig;
  TIM_OC_InitTypeDef sConfigOC;

  htim2.Instance = TIM2;
  htim2.Init.Prescaler = 0;
  htim2.Init.CounterMode = TIM_COUNTERMODE_UP;
  htim2.Init.Period = 5400;//3600;
  htim2.Init.ClockDivision = TIM_CLOCKDIVISION_DIV1;
  htim2.Init.AutoReloadPreload = TIM_AUTORELOAD_PRELOAD_ENABLE;//DISABLE;
  if (HAL_TIM_Base_Init(&htim2) != HAL_OK)
  {
    _Error_Handler(__FILE__, __LINE__);
  }

  sClockSourceConfig.ClockSource = TIM_CLOCKSOURCE_INTERNAL;
  if (HAL_TIM_ConfigClockSource(&htim2, &sClockSourceConfig) != HAL_OK)
  {
    _Error_Handler(__FILE__, __LINE__);
  }

  if (HAL_TIM_PWM_Init(&htim2) != HAL_OK)
  {
    _Error_Handler(__FILE__, __LINE__);
  }

  sMasterConfig.MasterOutputTrigger = TIM_TRGO_RESET;
  sMasterConfig.MasterSlaveMode = TIM_MASTERSLAVEMODE_DISABLE;
  if (HAL_TIMEx_MasterConfigSynchronization(&htim2, &sMasterConfig) != HAL_OK)
  {
    _Error_Handler(__FILE__, __LINE__);
  }

  sConfigOC.OCMode = TIM_OCMODE_PWM1;
  sConfigOC.Pulse = 0;
  sConfigOC.OCPolarity = TIM_OCPOLARITY_LOW;
  sConfigOC.OCFastMode = TIM_OCFAST_DISABLE;
  if (HAL_TIM_PWM_ConfigChannel(&htim2, &sConfigOC, TIM_CHANNEL_4) != HAL_OK)
  {
    _Error_Handler(__FILE__, __LINE__);
  }

  HAL_TIM_MspPostInit(&htim2);

}

/* TIM3 init function */
static void MX_TIM3_Init(void)
{

  TIM_ClockConfigTypeDef sClockSourceConfig;
  TIM_MasterConfigTypeDef sMasterConfig;
  TIM_IC_InitTypeDef sConfigIC;

  htim3.Instance = TIM3;
  htim3.Init.Prescaler = 107;//71;
  htim3.Init.CounterMode = TIM_COUNTERMODE_UP;
  htim3.Init.Period = 0xFFFF;
  htim3.Init.ClockDivision = TIM_CLOCKDIVISION_DIV1;
  htim3.Init.AutoReloadPreload = TIM_AUTORELOAD_PRELOAD_DISABLE;
  if (HAL_TIM_Base_Init(&htim3) != HAL_OK)
  {
    _Error_Handler(__FILE__, __LINE__);
  }

  sClockSourceConfig.ClockSource = TIM_CLOCKSOURCE_INTERNAL;
  if (HAL_TIM_ConfigClockSource(&htim3, &sClockSourceConfig) != HAL_OK)
  {
    _Error_Handler(__FILE__, __LINE__);
  }

  if (HAL_TIM_IC_Init(&htim3) != HAL_OK)
  {
    _Error_Handler(__FILE__, __LINE__);
  }

  sMasterConfig.MasterOutputTrigger = TIM_TRGO_RESET;
  sMasterConfig.MasterSlaveMode = TIM_MASTERSLAVEMODE_DISABLE;
  if (HAL_TIMEx_MasterConfigSynchronization(&htim3, &sMasterConfig) != HAL_OK)
  {
    _Error_Handler(__FILE__, __LINE__);
  }

  sConfigIC.ICPolarity = TIM_INPUTCHANNELPOLARITY_FALLING;
  sConfigIC.ICSelection = TIM_ICSELECTION_DIRECTTI;
  sConfigIC.ICPrescaler = TIM_ICPSC_DIV1;
  sConfigIC.ICFilter = 15;
  if (HAL_TIM_IC_ConfigChannel(&htim3, &sConfigIC, TIM_CHANNEL_1) != HAL_OK)
  {
    _Error_Handler(__FILE__, __LINE__);
  }

  if (HAL_TIM_IC_ConfigChannel(&htim3, &sConfigIC, TIM_CHANNEL_2) != HAL_OK)
  {
    _Error_Handler(__FILE__, __LINE__);
  }

}

/* TIM4 init function */
static void MX_TIM4_Init(void)
{

  TIM_ClockConfigTypeDef sClockSourceConfig;
  TIM_MasterConfigTypeDef sMasterConfig;
  TIM_OC_InitTypeDef sConfigOC;

  htim4.Instance = TIM4;
  htim4.Init.Prescaler = 107;//71;
  htim4.Init.CounterMode = TIM_COUNTERMODE_UP;
  htim4.Init.Period = 0xFFFF;
  htim4.Init.ClockDivision = TIM_CLOCKDIVISION_DIV1;
  htim4.Init.AutoReloadPreload = TIM_AUTORELOAD_PRELOAD_ENABLE;
  if (HAL_TIM_Base_Init(&htim4) != HAL_OK)
  {
    _Error_Handler(__FILE__, __LINE__);
  }

  sClockSourceConfig.ClockSource = TIM_CLOCKSOURCE_INTERNAL;
  if (HAL_TIM_ConfigClockSource(&htim4, &sClockSourceConfig) != HAL_OK)
  {
    _Error_Handler(__FILE__, __LINE__);
  }

  if (HAL_TIM_OC_Init(&htim4) != HAL_OK)
  {
    _Error_Handler(__FILE__, __LINE__);
  }

  sMasterConfig.MasterOutputTrigger = TIM_TRGO_RESET;
  sMasterConfig.MasterSlaveMode = TIM_MASTERSLAVEMODE_DISABLE;
  if (HAL_TIMEx_MasterConfigSynchronization(&htim4, &sMasterConfig) != HAL_OK)
  {
    _Error_Handler(__FILE__, __LINE__);
  }

  sConfigOC.OCMode = TIM_OCMODE_TIMING;
  sConfigOC.Pulse = 300;
  sConfigOC.OCPolarity = TIM_OCPOLARITY_HIGH;
  sConfigOC.OCFastMode = TIM_OCFAST_DISABLE;
  if (HAL_TIM_OC_ConfigChannel(&htim4, &sConfigOC, TIM_CHANNEL_3) != HAL_OK)
  {
    _Error_Handler(__FILE__, __LINE__);
  }

}

/* TIM6 init function */
static void MX_TIM6_Init(void)
{

  TIM_MasterConfigTypeDef sMasterConfig;

  htim6.Instance = TIM6;
  htim6.Init.Prescaler = 107;//71;
  htim6.Init.CounterMode = TIM_COUNTERMODE_UP;
  htim6.Init.Period = 5000;
  htim6.Init.AutoReloadPreload = TIM_AUTORELOAD_PRELOAD_DISABLE;
  if (HAL_TIM_Base_Init(&htim6) != HAL_OK)
  {
    _Error_Handler(__FILE__, __LINE__);
  }

  sMasterConfig.MasterOutputTrigger = TIM_TRGO_RESET;
  sMasterConfig.MasterSlaveMode = TIM_MASTERSLAVEMODE_DISABLE;
  if (HAL_TIMEx_MasterConfigSynchronization(&htim6, &sMasterConfig) != HAL_OK)
  {
    _Error_Handler(__FILE__, __LINE__);
  }

}

/* TIM7 init function */
static void MX_TIM7_Init(void)
{

  TIM_MasterConfigTypeDef sMasterConfig;

  htim7.Instance = TIM7;
  htim7.Init.Prescaler = 107;//71;
  htim7.Init.CounterMode = TIM_COUNTERMODE_UP;
  htim7.Init.Period = 1000;
  htim7.Init.AutoReloadPreload = TIM_AUTORELOAD_PRELOAD_DISABLE;
  if (HAL_TIM_Base_Init(&htim7) != HAL_OK)
  {
    _Error_Handler(__FILE__, __LINE__);
  }

  sMasterConfig.MasterOutputTrigger = TIM_TRGO_RESET;
  sMasterConfig.MasterSlaveMode = TIM_MASTERSLAVEMODE_DISABLE;
  if (HAL_TIMEx_MasterConfigSynchronization(&htim7, &sMasterConfig) != HAL_OK)
  {
    _Error_Handler(__FILE__, __LINE__);
  }

}

/* UART4 init function */
static void MX_UART4_Init(void)
{

  huart4.Instance = UART4;
  huart4.Init.BaudRate = 230400;
  huart4.Init.WordLength = UART_WORDLENGTH_8B;
  huart4.Init.StopBits = UART_STOPBITS_1;
  huart4.Init.Parity = UART_PARITY_NONE;
  huart4.Init.Mode = UART_MODE_TX_RX;
  huart4.Init.HwFlowCtl = UART_HWCONTROL_NONE;
  huart4.Init.OverSampling = UART_OVERSAMPLING_16;
  if (HAL_UART_Init(&huart4) != HAL_OK)
  {
    _Error_Handler(__FILE__, __LINE__);
  }

}

/* USART1 init function */
static void MX_USART1_UART_Init(void)
{

  huart1.Instance = USART1;
  huart1.Init.BaudRate = 115200; //76800;//
  huart1.Init.WordLength = UART_WORDLENGTH_8B;
  huart1.Init.StopBits = UART_STOPBITS_1;
  huart1.Init.Parity = UART_PARITY_NONE;
  huart1.Init.Mode = UART_MODE_TX_RX;
  huart1.Init.HwFlowCtl = UART_HWCONTROL_NONE;
  huart1.Init.OverSampling = UART_OVERSAMPLING_16;
  if (HAL_UART_Init(&huart1) != HAL_OK)
  {
    _Error_Handler(__FILE__, __LINE__);
  }

}

static void MX_DMA_Init(void)
{
  /* DMA controller clock enable */
  __HAL_RCC_DMA1_CLK_ENABLE();
  __HAL_RCC_DMA2_CLK_ENABLE();

  /* Configure DMA request hdma_memtomem_dma1_channel6 on DMA1_Channel6 */
  hdma_memtomem_dma1_channel6.Instance = DMA1_Channel6;
  hdma_memtomem_dma1_channel6.Init.Direction = DMA_MEMORY_TO_MEMORY;
  hdma_memtomem_dma1_channel6.Init.PeriphInc = DMA_PINC_ENABLE;
  hdma_memtomem_dma1_channel6.Init.MemInc = DMA_MINC_ENABLE;
  hdma_memtomem_dma1_channel6.Init.PeriphDataAlignment = DMA_PDATAALIGN_WORD;
  hdma_memtomem_dma1_channel6.Init.MemDataAlignment = DMA_MDATAALIGN_WORD;
  hdma_memtomem_dma1_channel6.Init.Mode = DMA_NORMAL;
  hdma_memtomem_dma1_channel6.Init.Priority = DMA_PRIORITY_LOW;
  if (HAL_DMA_Init(&hdma_memtomem_dma1_channel6) != HAL_OK)
  {
    _Error_Handler(__FILE__, __LINE__);
  }

}

/** Configure pins as
        * Analog
        * Input
        * Output
        * EVENT_OUT
        * EXTI
*/
static void MX_GPIO_Init(void)
{

  GPIO_InitTypeDef GPIO_InitStruct;

  /* GPIO Ports Clock Enable */
  __HAL_RCC_GPIOC_CLK_ENABLE();
  __HAL_RCC_GPIOD_CLK_ENABLE();
  __HAL_RCC_GPIOA_CLK_ENABLE();
  __HAL_RCC_GPIOB_CLK_ENABLE();

  /*Configure GPIO pin Output Level */
  HAL_GPIO_WritePin(GPIOC, EVFL_Pin|AVFL_Pin|WP_EPROM_Pin, GPIO_PIN_RESET);

  /*Configure GPIO pin Output Level */
  HAL_GPIO_WritePin(GPIOB, TstPoint_1_Pin|EVFR_Pin|AVFR_Pin|IN_DIFF_Pin
                          |IN_DBR_Pin, GPIO_PIN_RESET);

  /*Configure GPIO pin Output Level */
  HAL_GPIO_WritePin(GPIOB, EN_5V_Pin|IN_WL_Pin, GPIO_PIN_SET);
//  HAL_GPIO_WritePin(GPIOB, IN_WL_Pin, GPIO_PIN_SET);

  /*Configure GPIO pin Output Level */
  HAL_GPIO_WritePin(IN_GNDF_GPIO_Port, IN_GNDF_Pin, GPIO_PIN_SET);

  /*Configure GPIO pin Output Level */
  HAL_GPIO_WritePin(CS_EPROM_GPIO_Port, CS_EPROM_Pin, GPIO_PIN_SET);

  /*Configure GPIO pins : EVFL_Pin AVFL_Pin WP_EPROM_Pin */
  GPIO_InitStruct.Pin = EVFL_Pin|AVFL_Pin|WP_EPROM_Pin;
  GPIO_InitStruct.Mode = GPIO_MODE_OUTPUT_PP;
  GPIO_InitStruct.Speed = GPIO_SPEED_FREQ_HIGH;
  HAL_GPIO_Init(GPIOC, &GPIO_InitStruct);

  /*Configure GPIO pins : TstPoint_1_Pin EN_5V_Pin EVFR_Pin AVFR_Pin
                           IN_DIFF_Pin IN_DBR_Pin IN_WL_Pin */
  GPIO_InitStruct.Pin = TstPoint_1_Pin|EN_5V_Pin|EVFR_Pin|AVFR_Pin
                          |IN_DIFF_Pin|IN_DBR_Pin|IN_WL_Pin;
  GPIO_InitStruct.Mode = GPIO_MODE_OUTPUT_PP;
  GPIO_InitStruct.Speed = GPIO_SPEED_FREQ_HIGH;
  HAL_GPIO_Init(GPIOB, &GPIO_InitStruct);

  /*Configure GPIO pin : IN_GNDF_Pin GPIOC */
  GPIO_InitStruct.Pin = IN_GNDF_Pin;
  GPIO_InitStruct.Mode = GPIO_MODE_OUTPUT_PP;
  GPIO_InitStruct.Speed = GPIO_SPEED_FREQ_HIGH;
  HAL_GPIO_Init(IN_GNDF_GPIO_Port, &GPIO_InitStruct);

  /*Configure GPIO pin : CS_EPROM_Pin GPIOD */
  GPIO_InitStruct.Pin = CS_EPROM_Pin;
  GPIO_InitStruct.Mode = GPIO_MODE_OUTPUT_PP;
  GPIO_InitStruct.Speed = GPIO_SPEED_FREQ_HIGH;
  HAL_GPIO_Init(CS_EPROM_GPIO_Port, &GPIO_InitStruct);

  /*Configure GPIO pin : PA8_Pin */
  HAL_GPIO_WritePin(MC1_TX_GPIO_Port, MC1_TX_Pin, GPIO_PIN_SET);
  GPIO_InitStruct.Pin = MC1_TX_Pin;
  GPIO_InitStruct.Mode = GPIO_MODE_OUTPUT_PP;
  GPIO_InitStruct.Speed = GPIO_SPEED_FREQ_HIGH;
  HAL_GPIO_Init(MC1_TX_GPIO_Port, &GPIO_InitStruct);
  /*Configure GPIO pin : PB6_Pin */
  GPIO_InitStruct.Pin = MC1_RX_Pin;
  GPIO_InitStruct.Mode = GPIO_MODE_IT_RISING_FALLING;
  GPIO_InitStruct.Pull = GPIO_PULLUP;
  HAL_GPIO_Init(MC1_RX_GPIO_Port, &GPIO_InitStruct);
}

/* USER CODE BEGIN 4 */
/* SPI1 init function */

/* USER CODE END 4 */

void _Error_Handler(char *file, int line)
{
  /* USER CODE BEGIN Error_Handler_Debug */
  /* User can add his own implementation to report the HAL error return state */
//  while(1) { }
  /* USER CODE END Error_Handler_Debug */
}

/************************ (C) COPYRIGHT STMicroelectronics *****END OF FILE****/
